VERSION 5.7 ;
  NOWIREEXTENSIONATPIN ON ;
  DIVIDERCHAR "/" ;
  BUSBITCHARS "[]" ;
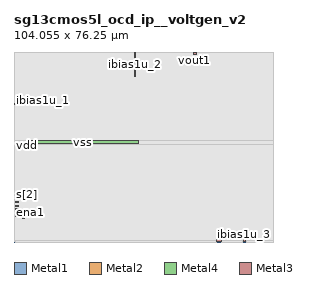
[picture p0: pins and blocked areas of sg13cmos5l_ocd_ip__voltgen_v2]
MACRO sg13cmos5l_ocd_ip__voltgen_v2
  CLASS BLOCK ;
  FOREIGN sg13cmos5l_ocd_ip__voltgen_v2 ;
  ORIGIN -7.925 66.420 ;
  SIZE 104.055 BY 76.250 ;
  PIN dvdd
    ANTENNAGATEAREA 0.420000 ;
    ANTENNADIFFAREA 31.308800 ;
    PORT
      LAYER Metal1 ;
        RECT 11.145 -57.090 12.145 -56.440 ;
    END
  END dvdd
  PIN dvss
    ANTENNAGATEAREA 1.000000 ;
    ANTENNADIFFAREA 26.090399 ;
    PORT
      LAYER Metal1 ;
        RECT 11.305 -46.425 12.305 -45.740 ;
    END
  END dvss
  PIN vdd
    ANTENNAGATEAREA 36.000000 ;
    ANTENNADIFFAREA 377.752960 ;
    PORT
      LAYER Metal1 ;
        RECT 9.175 -28.045 10.175 -27.045 ;
    END
  END vdd
  PIN s[2]
    ANTENNAGATEAREA 0.483600 ;
    ANTENNADIFFAREA 2.015400 ;
    PORT
      LAYER Metal2 ;
        RECT 8.555 -47.650 9.555 -47.275 ;
    END
  END s[2]
  PIN s[1]
    ANTENNAGATEAREA 0.483600 ;
    ANTENNADIFFAREA 2.015400 ;
    PORT
      LAYER Metal2 ;
        RECT 8.545 -49.115 9.545 -48.725 ;
    END
  END s[1]
  PIN s[0]
    ANTENNAGATEAREA 0.483600 ;
    ANTENNADIFFAREA 2.015400 ;
    PORT
      LAYER Metal2 ;
        RECT 8.555 -50.545 9.555 -50.160 ;
    END
  END s[0]
  PIN vbg
    ANTENNAGATEAREA 10.000000 ;
    PORT
      LAYER Metal2 ;
        RECT 8.225 -11.345 9.780 -10.710 ;
    END
  END vbg
  PIN vss
    ANTENNAGATEAREA 18.000000 ;
    ANTENNADIFFAREA 311.049530 ;
    PORT
      LAYER Metal4 ;
        RECT 13.145 -27.000 57.815 -25.760 ;
    END
  END vss
  PIN ibias1u_1
    ANTENNADIFFAREA 3.800000 ;
    PORT
      LAYER Metal2 ;
        RECT 8.350 -9.970 9.350 -9.545 ;
    END
  END ibias1u_1
  PIN vout2
    ANTENNAGATEAREA 32.000000 ;
    ANTENNADIFFAREA 8.160000 ;
    PORT
      LAYER Metal3 ;
        RECT 89.335 -66.405 91.080 -65.310 ;
    END
  END vout2
  PIN ibias1u_2
    ANTENNADIFFAREA 3.800000 ;
    PORT
      LAYER Metal3 ;
        RECT 56.225 0.010 56.530 9.815 ;
    END
  END ibias1u_2
  PIN ena
    ANTENNAGATEAREA 4.483600 ;
    ANTENNADIFFAREA 2.015400 ;
    PORT
      LAYER Metal2 ;
        RECT 8.565 -51.990 9.565 -51.585 ;
    END
  END ena
  PIN vout1
    ANTENNAGATEAREA 10.000000 ;
    ANTENNADIFFAREA 7.200000 ;
    PORT
      LAYER Metal3 ;
        RECT 80.010 8.830 81.010 9.830 ;
    END
  END vout1
  PIN ena1
    ANTENNAGATEAREA 4.483600 ;
    ANTENNADIFFAREA 2.015400 ;
    PORT
      LAYER Metal2 ;
        RECT 8.565 -54.865 9.565 -54.485 ;
    END
  END ena1
  PIN ena2
    ANTENNAGATEAREA 4.483600 ;
    ANTENNADIFFAREA 2.015400 ;
    PORT
      LAYER Metal2 ;
        RECT 8.565 -53.425 9.565 -52.950 ;
    END
  END ena2
  PIN ibias1u_3
    ANTENNADIFFAREA 2.720000 ;
    PORT
      LAYER Metal3 ;
        RECT 99.860 -66.415 100.860 -65.415 ;
    END
  END ibias1u_3
  PIN high
    ANTENNAGATEAREA 4.483600 ;
    ANTENNADIFFAREA 2.015400 ;
    PORT
      LAYER Metal2 ;
        RECT 8.575 -56.195 9.575 -55.805 ;
    END
  END high
  OBS
      LAYER GatPoly ;
        RECT 8.495 -65.755 110.495 0.775 ;
      LAYER Metal1 ;
        RECT 7.975 -26.865 111.975 9.765 ;
        RECT 7.975 -28.225 8.995 -26.865 ;
        RECT 10.355 -28.225 111.975 -26.865 ;
        RECT 7.975 -45.560 111.975 -28.225 ;
        RECT 7.975 -46.605 11.125 -45.560 ;
        RECT 12.485 -46.605 111.975 -45.560 ;
        RECT 7.975 -56.260 111.975 -46.605 ;
        RECT 7.975 -57.270 10.965 -56.260 ;
        RECT 12.325 -57.270 111.975 -56.260 ;
        RECT 7.975 -66.405 111.975 -57.270 ;
      LAYER Metal2 ;
        RECT 7.925 -9.335 111.975 9.765 ;
        RECT 7.925 -10.180 8.140 -9.335 ;
        RECT 9.560 -10.180 111.975 -9.335 ;
        RECT 7.925 -10.500 111.975 -10.180 ;
        RECT 7.925 -11.555 8.015 -10.500 ;
        RECT 9.990 -11.555 111.975 -10.500 ;
        RECT 7.925 -47.065 111.975 -11.555 ;
        RECT 7.925 -47.860 8.345 -47.065 ;
        RECT 9.765 -47.860 111.975 -47.065 ;
        RECT 7.925 -48.515 111.975 -47.860 ;
        RECT 7.925 -49.325 8.335 -48.515 ;
        RECT 9.755 -49.325 111.975 -48.515 ;
        RECT 7.925 -49.950 111.975 -49.325 ;
        RECT 7.925 -50.755 8.345 -49.950 ;
        RECT 9.765 -50.755 111.975 -49.950 ;
        RECT 7.925 -51.375 111.975 -50.755 ;
        RECT 7.925 -52.200 8.355 -51.375 ;
        RECT 9.775 -52.200 111.975 -51.375 ;
        RECT 7.925 -52.740 111.975 -52.200 ;
        RECT 7.925 -53.635 8.355 -52.740 ;
        RECT 9.775 -53.635 111.975 -52.740 ;
        RECT 7.925 -54.275 111.975 -53.635 ;
        RECT 7.925 -55.075 8.355 -54.275 ;
        RECT 9.775 -55.075 111.975 -54.275 ;
        RECT 7.925 -55.595 111.975 -55.075 ;
        RECT 7.925 -56.405 8.365 -55.595 ;
        RECT 9.785 -56.405 111.975 -55.595 ;
        RECT 7.925 -66.405 111.975 -56.405 ;
      LAYER Metal3 ;
        RECT 8.390 -0.200 56.015 9.765 ;
        RECT 56.740 8.620 79.800 9.765 ;
        RECT 81.220 8.620 111.980 9.765 ;
        RECT 56.740 -0.200 111.980 8.620 ;
        RECT 8.390 -65.100 111.980 -0.200 ;
        RECT 8.390 -66.420 89.125 -65.100 ;
        RECT 91.290 -65.205 111.980 -65.100 ;
        RECT 91.290 -66.420 99.650 -65.205 ;
        RECT 101.070 -66.420 111.980 -65.205 ;
      LAYER Metal4 ;
        RECT 7.950 -25.550 111.970 9.765 ;
        RECT 7.950 -27.210 12.935 -25.550 ;
        RECT 58.025 -27.210 111.970 -25.550 ;
        RECT 7.950 -65.800 111.970 -27.210 ;
  END
END sg13cmos5l_ocd_ip__voltgen_v2
END LIBRARY

